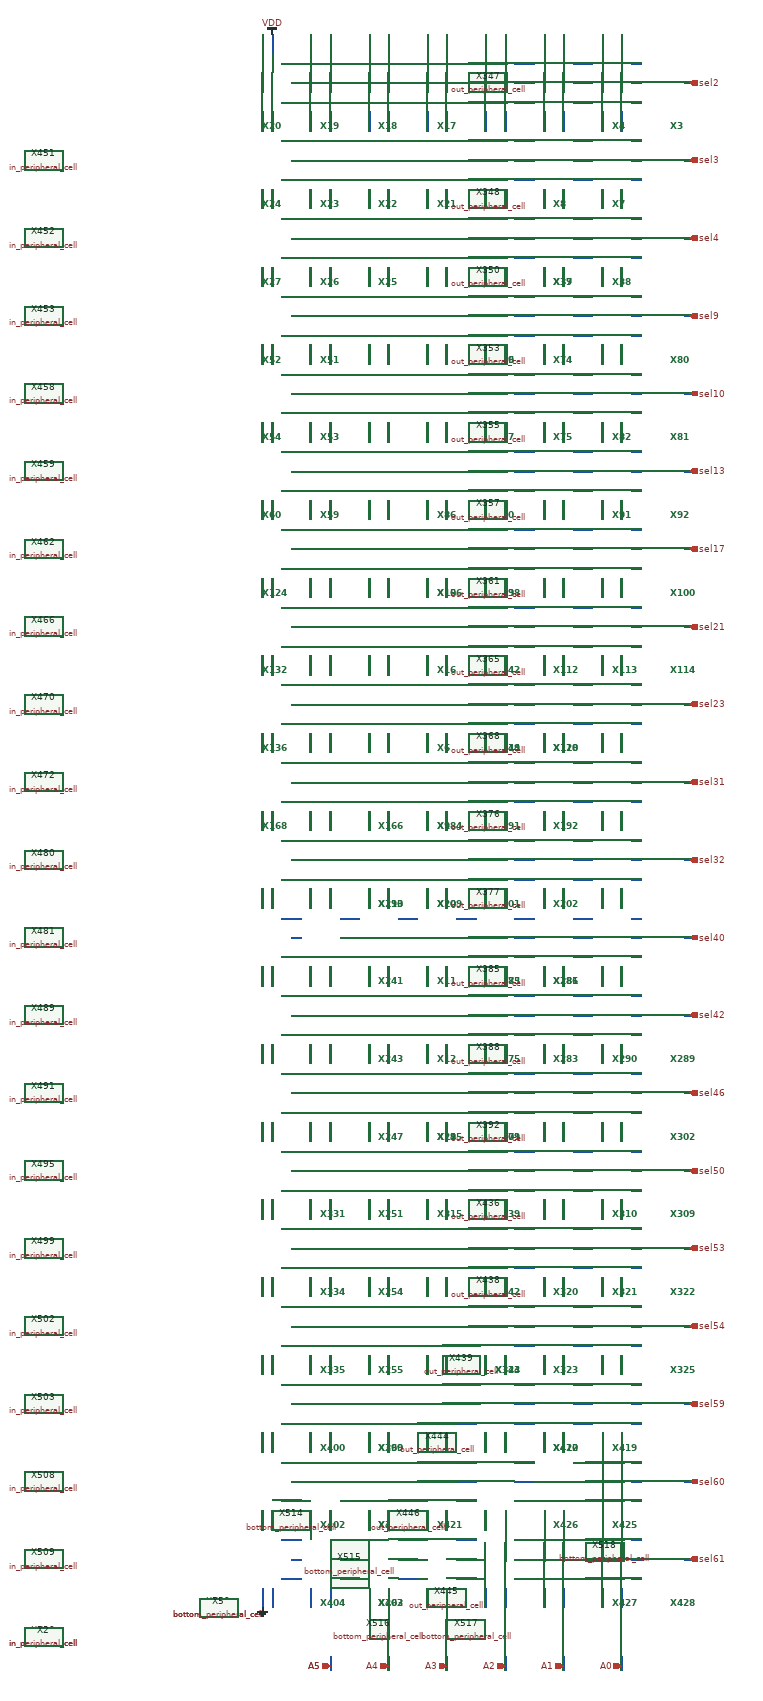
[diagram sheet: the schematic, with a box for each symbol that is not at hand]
v {xschem version=2.9.9 file_version=1.2 }
G {}
K {}
V {}
S {}
E {}
N 7700 7730 7700 7760 { lab=A5}
N 7820 7730 7820 7760 { lab=A4}
N 7940 7730 7940 7760 { lab=A3}
N 8060 7730 8060 7760 { lab=A2}
N 8180 7730 8180 7760 { lab=A1}
N 8300 7730 8300 7760 { lab=A0}
N 8430 7530 8450 7530 { lab=sel61}
N 8430 7370 8450 7370 { lab=sel60}
N 8430 7210 8450 7210 { lab=sel59}
N 8430 7050 8450 7050 { lab=sel54}
N 8430 6890 8450 6890 { lab=sel53}
N 8430 6730 8450 6730 { lab=sel50}
N 8430 6570 8450 6570 { lab=sel46}
N 8430 6410 8450 6410 { lab=sel42}
N 8430 6250 8450 6250 { lab=sel40}
N 8430 5930 8450 5930 { lab=sel31}
N 8430 5770 8450 5770 { lab=sel23}
N 8430 5450 8450 5450 { lab=sel17}
N 8430 5290 8450 5290 { lab=sel13}
N 8430 5130 8450 5130 { lab=sel10}
N 8430 4970 8450 4970 { lab=sel9}
N 8430 4810 8450 4810 { lab=sel4}
N 8430 4650 8450 4650 { lab=sel3}
N 8430 4490 8450 4490 { lab=sel2}
N 7560 4390 7560 4430 { lab=#net1}
N 7580 4390 7580 4430 { lab=VDD}
N 7660 4390 7660 4430 { lab=#net2}
N 7700 4390 7700 4430 { lab=#net3}
N 7780 4390 7780 4430 { lab=#net4}
N 7820 4390 7820 4430 { lab=#net5}
N 7900 4390 7900 4430 { lab=#net6}
N 7940 4390 7940 4430 { lab=#net7}
N 8020 4390 8020 4430 { lab=#net8}
N 8060 4390 8060 4430 { lab=#net9}
N 8140 4390 8140 4430 { lab=#net10}
N 8180 4390 8180 4430 { lab=#net11}
N 8260 4390 8260 4430 { lab=#net12}
N 8300 4390 8300 4430 { lab=#net13}
N 7600 4450 7640 4450 { lab=#net14}
N 7600 4530 7640 4530 { lab=#net15}
N 7720 4450 7760 4450 { lab=#net16}
N 7720 4490 7760 4490 { lab=#net17}
N 7720 4530 7760 4530 { lab=#net18}
N 7840 4450 7880 4450 { lab=#net19}
N 7840 4490 7880 4490 { lab=#net20}
N 7840 4530 7880 4530 { lab=#net21}
N 7960 4450 8000 4450 { lab=#net22}
N 7960 4490 8000 4490 { lab=#net23}
N 7960 4530 8000 4530 { lab=#net24}
N 8080 4450 8120 4450 { lab=#net25}
N 8080 4490 8120 4490 { lab=#net26}
N 8080 4530 8120 4530 { lab=#net27}
N 8200 4450 8240 4450 { lab=#net28}
N 8200 4490 8240 4490 { lab=#net29}
N 8200 4530 8240 4530 { lab=#net30}
N 8320 4490 8340 4490 { lab=#net31}
N 8320 4530 8340 4530 { lab=#net32}
N 7560 4550 7560 4590 { lab=#net33}
N 7580 4550 7580 4590 { lab=#net34}
N 7660 4550 7660 4590 { lab=#net35}
N 7700 4550 7700 4590 { lab=#net36}
N 7780 4550 7780 4590 { lab=#net37}
N 7820 4550 7820 4590 { lab=#net38}
N 7900 4550 7900 4590 { lab=#net39}
N 7940 4550 7940 4590 { lab=#net40}
N 8020 4550 8020 4590 { lab=#net41}
N 8060 4550 8060 4590 { lab=#net42}
N 8140 4550 8140 4590 { lab=#net43}
N 8180 4550 8180 4590 { lab=#net44}
N 8260 4550 8260 4590 { lab=#net45}
N 8300 4550 8300 4590 { lab=#net46}
N 7600 4610 7640 4610 { lab=#net47}
N 7600 4690 7640 4690 { lab=#net48}
N 7720 4610 7760 4610 { lab=#net49}
N 7720 4650 7760 4650 { lab=#net50}
N 7720 4690 7760 4690 { lab=#net51}
N 7840 4610 7880 4610 { lab=#net52}
N 7840 4650 7880 4650 { lab=#net53}
N 7840 4690 7880 4690 { lab=#net54}
N 7960 4610 8000 4610 { lab=#net55}
N 7960 4650 8000 4650 { lab=#net56}
N 7960 4690 8000 4690 { lab=#net57}
N 8080 4610 8120 4610 { lab=#net58}
N 8080 4650 8120 4650 { lab=#net59}
N 8080 4690 8120 4690 { lab=#net60}
N 8200 4610 8240 4610 { lab=#net61}
N 8200 4650 8240 4650 { lab=#net62}
N 8200 4690 8240 4690 { lab=#net63}
N 8320 4650 8340 4650 { lab=#net64}
N 8320 4690 8340 4690 { lab=#net65}
N 7560 4710 7560 4750 { lab=#net66}
N 7580 4710 7580 4750 { lab=#net67}
N 7660 4710 7660 4750 { lab=#net68}
N 7700 4710 7700 4750 { lab=#net69}
N 7780 4710 7780 4750 { lab=#net70}
N 7820 4710 7820 4750 { lab=#net71}
N 7900 4710 7900 4750 { lab=#net72}
N 7940 4710 7940 4750 { lab=#net73}
N 8020 4710 8020 4750 { lab=#net74}
N 8060 4710 8060 4750 { lab=#net75}
N 8140 4710 8140 4750 { lab=#net76}
N 8180 4710 8180 4750 { lab=#net77}
N 8260 4710 8260 4750 { lab=#net78}
N 8300 4710 8300 4750 { lab=#net79}
N 7600 4770 7640 4770 { lab=#net80}
N 7720 4770 7760 4770 { lab=#net81}
N 7720 4810 7760 4810 { lab=#net82}
N 7840 4770 7880 4770 { lab=#net83}
N 7840 4810 7880 4810 { lab=#net84}
N 7960 4770 8000 4770 { lab=#net85}
N 7960 4810 8000 4810 { lab=#net86}
N 8080 4770 8120 4770 { lab=#net87}
N 8080 4810 8120 4810 { lab=#net88}
N 8200 4770 8240 4770 { lab=#net89}
N 8200 4810 8240 4810 { lab=#net90}
N 8320 4810 8340 4810 { lab=#net91}
N 7560 4870 7560 4910 { lab=#net92}
N 7580 4870 7580 4910 { lab=#net93}
N 7660 4870 7660 4910 { lab=#net94}
N 7700 4870 7700 4910 { lab=#net95}
N 7780 4870 7780 4910 { lab=#net96}
N 7820 4870 7820 4910 { lab=#net97}
N 7900 4870 7900 4910 { lab=#net98}
N 7940 4870 7940 4910 { lab=#net99}
N 8020 4870 8020 4910 { lab=#net100}
N 8060 4870 8060 4910 { lab=#net101}
N 8140 4870 8140 4910 { lab=#net102}
N 8180 4870 8180 4910 { lab=#net103}
N 8260 4870 8260 4910 { lab=#net104}
N 8300 4870 8300 4910 { lab=#net105}
N 7600 4930 7640 4930 { lab=#net106}
N 7600 5010 7640 5010 { lab=#net107}
N 7720 4930 7760 4930 { lab=#net108}
N 7720 4970 7760 4970 { lab=#net109}
N 7720 5010 7760 5010 { lab=#net110}
N 7840 4930 7880 4930 { lab=#net111}
N 7840 4970 7880 4970 { lab=#net112}
N 7840 5010 7880 5010 { lab=#net113}
N 7960 4930 8000 4930 { lab=#net114}
N 7960 4970 8000 4970 { lab=#net115}
N 7960 5010 8000 5010 { lab=#net116}
N 8080 4930 8120 4930 { lab=#net117}
N 8080 4970 8120 4970 { lab=#net118}
N 8080 5010 8120 5010 { lab=#net119}
N 8200 4930 8240 4930 { lab=#net120}
N 8200 4970 8240 4970 { lab=#net121}
N 8200 5010 8240 5010 { lab=#net122}
N 8320 4970 8340 4970 { lab=#net123}
N 8320 5010 8340 5010 { lab=#net124}
N 7560 5030 7560 5070 { lab=#net125}
N 7580 5030 7580 5070 { lab=#net126}
N 7660 5030 7660 5070 { lab=#net127}
N 7700 5030 7700 5070 { lab=#net128}
N 7780 5030 7780 5070 { lab=#net129}
N 7820 5030 7820 5070 { lab=#net130}
N 7900 5030 7900 5070 { lab=#net131}
N 7940 5030 7940 5070 { lab=#net132}
N 8020 5030 8020 5070 { lab=#net133}
N 8060 5030 8060 5070 { lab=#net134}
N 8140 5030 8140 5070 { lab=#net135}
N 8180 5030 8180 5070 { lab=#net136}
N 8260 5030 8260 5070 { lab=#net137}
N 8300 5030 8300 5070 { lab=#net138}
N 7600 5090 7640 5090 { lab=#net139}
N 7720 5090 7760 5090 { lab=#net140}
N 7720 5130 7760 5130 { lab=#net141}
N 7840 5090 7880 5090 { lab=#net142}
N 7840 5130 7880 5130 { lab=#net143}
N 7960 5090 8000 5090 { lab=#net144}
N 7960 5130 8000 5130 { lab=#net145}
N 8080 5090 8120 5090 { lab=#net146}
N 8080 5130 8120 5130 { lab=#net147}
N 8200 5090 8240 5090 { lab=#net148}
N 8200 5130 8240 5130 { lab=#net149}
N 8320 5130 8340 5130 { lab=#net150}
N 7560 5190 7560 5230 { lab=#net151}
N 7580 5190 7580 5230 { lab=#net152}
N 7660 5190 7660 5230 { lab=#net153}
N 7700 5190 7700 5230 { lab=#net154}
N 7780 5190 7780 5230 { lab=#net155}
N 7820 5190 7820 5230 { lab=#net156}
N 7900 5190 7900 5230 { lab=#net157}
N 7940 5190 7940 5230 { lab=#net158}
N 8020 5190 8020 5230 { lab=#net159}
N 8060 5190 8060 5230 { lab=#net160}
N 8140 5190 8140 5230 { lab=#net161}
N 8180 5190 8180 5230 { lab=#net162}
N 8260 5190 8260 5230 { lab=#net163}
N 8300 5190 8300 5230 { lab=#net164}
N 7600 5250 7640 5250 { lab=#net165}
N 7720 5250 7760 5250 { lab=#net166}
N 7720 5290 7760 5290 { lab=#net167}
N 7840 5250 7880 5250 { lab=#net168}
N 7840 5290 7880 5290 { lab=#net169}
N 7960 5250 8000 5250 { lab=#net170}
N 7960 5290 8000 5290 { lab=#net171}
N 8080 5250 8120 5250 { lab=#net172}
N 8080 5290 8120 5290 { lab=#net173}
N 8200 5250 8240 5250 { lab=#net174}
N 8200 5290 8240 5290 { lab=#net175}
N 8320 5290 8340 5290 { lab=#net176}
N 7560 5350 7560 5390 { lab=#net177}
N 7580 5350 7580 5390 { lab=#net178}
N 7660 5350 7660 5390 { lab=#net179}
N 7700 5350 7700 5390 { lab=#net180}
N 7780 5350 7780 5390 { lab=#net181}
N 7820 5350 7820 5390 { lab=#net182}
N 7900 5350 7900 5390 { lab=#net183}
N 7940 5350 7940 5390 { lab=#net184}
N 8020 5350 8020 5390 { lab=#net185}
N 8060 5350 8060 5390 { lab=#net186}
N 8140 5350 8140 5390 { lab=#net187}
N 8180 5350 8180 5390 { lab=#net188}
N 8260 5350 8260 5390 { lab=#net189}
N 8300 5350 8300 5390 { lab=#net190}
N 7600 5410 7640 5410 { lab=#net191}
N 7720 5410 7760 5410 { lab=#net192}
N 7720 5450 7760 5450 { lab=#net193}
N 7840 5410 7880 5410 { lab=#net194}
N 7840 5450 7880 5450 { lab=#net195}
N 7960 5410 8000 5410 { lab=#net196}
N 7960 5450 8000 5450 { lab=#net197}
N 8080 5410 8120 5410 { lab=#net198}
N 8080 5450 8120 5450 { lab=#net199}
N 8200 5410 8240 5410 { lab=#net200}
N 8200 5450 8240 5450 { lab=#net201}
N 8320 5450 8340 5450 { lab=#net202}
N 7560 5510 7560 5550 { lab=#net203}
N 7580 5510 7580 5550 { lab=#net204}
N 7660 5510 7660 5550 { lab=#net205}
N 7700 5510 7700 5550 { lab=#net206}
N 7900 5510 7900 5550 { lab=#net209}
N 7940 5510 7940 5550 { lab=#net210}
N 8020 5510 8020 5550 { lab=#net211}
N 8060 5510 8060 5550 { lab=#net212}
N 8140 5510 8140 5550 { lab=#net213}
N 8180 5510 8180 5550 { lab=#net214}
N 8260 5510 8260 5550 { lab=#net215}
N 8300 5510 8300 5550 { lab=#net216}
N 7600 5570 7640 5570 { lab=#net217}
N 7720 5570 7760 5570 { lab=#net218}
N 7840 5570 7880 5570 { lab=#net219}
N 7960 5570 8000 5570 { lab=#net220}
N 8080 5570 8120 5570 { lab=#net221}
N 8200 5570 8240 5570 { lab=#net222}
N 7560 5670 7560 5710 { lab=#net223}
N 7580 5670 7580 5710 { lab=#net224}
N 7660 5670 7660 5710 { lab=#net225}
N 7700 5670 7700 5710 { lab=#net226}
N 7900 5670 7900 5710 { lab=#net229}
N 7940 5670 7940 5710 { lab=#net230}
N 8020 5670 8020 5710 { lab=#net231}
N 8060 5670 8060 5710 { lab=#net232}
N 8140 5670 8140 5710 { lab=#net233}
N 8180 5670 8180 5710 { lab=#net234}
N 8260 5670 8260 5710 { lab=#net235}
N 8300 5670 8300 5710 { lab=#net236}
N 7600 5730 7640 5730 { lab=#net237}
N 7720 5730 7760 5730 { lab=#net238}
N 7720 5770 7760 5770 { lab=#net239}
N 7840 5730 7880 5730 { lab=#net240}
N 7840 5770 7880 5770 { lab=#net241}
N 7960 5730 8000 5730 { lab=#net242}
N 7960 5770 8000 5770 { lab=#net243}
N 8080 5730 8120 5730 { lab=#net244}
N 8080 5770 8120 5770 { lab=#net245}
N 8200 5730 8240 5730 { lab=#net246}
N 8200 5770 8240 5770 { lab=#net247}
N 8320 5770 8340 5770 { lab=#net248}
N 7560 5830 7560 5870 { lab=#net249}
N 7580 5830 7580 5870 { lab=#net250}
N 7660 5830 7660 5870 { lab=#net251}
N 7700 5830 7700 5870 { lab=#net252}
N 7900 5830 7900 5870 { lab=#net255}
N 7940 5830 7940 5870 { lab=#net256}
N 8020 5830 8020 5870 { lab=#net257}
N 8060 5830 8060 5870 { lab=#net258}
N 8140 5830 8140 5870 { lab=#net259}
N 8180 5830 8180 5870 { lab=#net260}
N 8260 5830 8260 5870 { lab=#net261}
N 8300 5830 8300 5870 { lab=#net262}
N 7600 5890 7640 5890 { lab=#net263}
N 7600 5970 7640 5970 { lab=#net264}
N 7720 5890 7760 5890 { lab=#net265}
N 7720 5930 7760 5930 { lab=#net266}
N 7720 5970 7760 5970 { lab=#net267}
N 7840 5890 7880 5890 { lab=#net268}
N 7840 5930 7880 5930 { lab=#net269}
N 7840 5970 7880 5970 { lab=#net270}
N 7960 5890 8000 5890 { lab=#net271}
N 7960 5930 8000 5930 { lab=#net272}
N 7960 5970 8000 5970 { lab=#net273}
N 8080 5890 8120 5890 { lab=#net274}
N 8080 5930 8120 5930 { lab=#net275}
N 8080 5970 8120 5970 { lab=#net276}
N 8200 5890 8240 5890 { lab=#net277}
N 8200 5930 8240 5930 { lab=#net278}
N 8200 5970 8240 5970 { lab=#net279}
N 8320 5930 8340 5930 { lab=#net280}
N 8320 5970 8340 5970 { lab=#net281}
N 7560 5990 7560 6030 { lab=#net282}
N 7580 5990 7580 6030 { lab=#net283}
N 7660 5990 7660 6030 { lab=#net284}
N 7700 5990 7700 6030 { lab=#net285}
N 7900 5990 7900 6030 { lab=#net288}
N 7940 5990 7940 6030 { lab=#net289}
N 8020 5990 8020 6030 { lab=#net290}
N 8060 5990 8060 6030 { lab=#net291}
N 8140 5990 8140 6030 { lab=#net292}
N 8180 5990 8180 6030 { lab=#net293}
N 8260 5990 8260 6030 { lab=#net294}
N 8300 5990 8300 6030 { lab=#net295}
N 7600 6050 7640 6050 { lab=#net296}
N 7720 6050 7760 6050 { lab=#net297}
N 7840 6050 7880 6050 { lab=#net298}
N 7960 6050 8000 6050 { lab=#net299}
N 8080 6050 8120 6050 { lab=#net300}
N 8200 6050 8240 6050 { lab=#net301}
N 7560 6150 7560 6190 { lab=#net302}
N 7580 6150 7580 6190 { lab=#net303}
N 7660 6150 7660 6190 { lab=#net304}
N 7700 6150 7700 6190 { lab=#net305}
N 7900 6150 7900 6190 { lab=#net308}
N 7940 6150 7940 6190 { lab=#net309}
N 8020 6150 8020 6190 { lab=#net310}
N 8060 6150 8060 6190 { lab=#net311}
N 8140 6150 8140 6190 { lab=#net312}
N 8180 6150 8180 6190 { lab=#net313}
N 8260 6150 8260 6190 { lab=#net314}
N 8300 6150 8300 6190 { lab=#net315}
N 7600 6210 7640 6210 { lab=#net316}
N 7720 6210 7760 6210 { lab=#net317}
N 7840 6210 7880 6210 { lab=#net318}
N 7960 6210 8000 6210 { lab=#net319}
N 8080 6210 8120 6210 { lab=#net320}
N 8200 6210 8240 6210 { lab=#net321}
N 7600 6210 7640 6210 { lab=#net316}
N 7720 6210 7760 6210 { lab=#net317}
N 7720 6250 7760 6250 { lab=#net322}
N 7840 6210 7880 6210 { lab=#net318}
N 7840 6250 7880 6250 { lab=#net323}
N 7960 6210 8000 6210 { lab=#net319}
N 7960 6250 8000 6250 { lab=#net324}
N 8080 6210 8120 6210 { lab=#net320}
N 8080 6250 8120 6250 { lab=#net325}
N 8200 6210 8240 6210 { lab=#net321}
N 8200 6250 8240 6250 { lab=#net326}
N 8320 6250 8340 6250 { lab=#net327}
N 7560 6310 7560 6350 { lab=#net328}
N 7580 6310 7580 6350 { lab=#net329}
N 7660 6310 7660 6350 { lab=#net330}
N 7700 6310 7700 6350 { lab=#net331}
N 7900 6310 7900 6350 { lab=#net334}
N 7940 6310 7940 6350 { lab=#net335}
N 8020 6310 8020 6350 { lab=#net336}
N 8060 6310 8060 6350 { lab=#net337}
N 8140 6310 8140 6350 { lab=#net338}
N 8180 6310 8180 6350 { lab=#net339}
N 8260 6310 8260 6350 { lab=#net340}
N 8300 6310 8300 6350 { lab=#net341}
N 7600 6370 7640 6370 { lab=#net342}
N 7720 6370 7760 6370 { lab=#net343}
N 7720 6410 7760 6410 { lab=#net344}
N 7840 6370 7880 6370 { lab=#net345}
N 7840 6410 7880 6410 { lab=#net346}
N 7960 6370 8000 6370 { lab=#net347}
N 7960 6410 8000 6410 { lab=#net348}
N 8080 6370 8120 6370 { lab=#net349}
N 8080 6410 8120 6410 { lab=#net350}
N 8200 6370 8240 6370 { lab=#net351}
N 8200 6410 8240 6410 { lab=#net352}
N 8320 6410 8340 6410 { lab=#net353}
N 7560 6470 7560 6510 { lab=#net354}
N 7580 6470 7580 6510 { lab=#net355}
N 7660 6470 7660 6510 { lab=#net356}
N 7700 6470 7700 6510 { lab=#net357}
N 7900 6470 7900 6510 { lab=#net360}
N 7940 6470 7940 6510 { lab=#net361}
N 8020 6470 8020 6510 { lab=#net362}
N 8060 6470 8060 6510 { lab=#net363}
N 8140 6470 8140 6510 { lab=#net364}
N 8180 6470 8180 6510 { lab=#net365}
N 8260 6470 8260 6510 { lab=#net366}
N 8300 6470 8300 6510 { lab=#net367}
N 7600 6530 7640 6530 { lab=#net368}
N 7720 6530 7760 6530 { lab=#net369}
N 7720 6570 7760 6570 { lab=#net370}
N 7840 6530 7880 6530 { lab=#net371}
N 7840 6570 7880 6570 { lab=#net372}
N 7960 6530 8000 6530 { lab=#net373}
N 7960 6570 8000 6570 { lab=#net374}
N 8080 6530 8120 6530 { lab=#net375}
N 8080 6570 8120 6570 { lab=#net376}
N 8200 6530 8240 6530 { lab=#net377}
N 8200 6570 8240 6570 { lab=#net378}
N 8320 6570 8340 6570 { lab=#net379}
N 7560 6630 7560 6670 { lab=#net380}
N 7580 6630 7580 6670 { lab=#net381}
N 7660 6630 7660 6670 { lab=#net382}
N 7700 6630 7700 6670 { lab=#net383}
N 7780 6630 7780 6670 { lab=#net384}
N 7820 6630 7820 6670 { lab=#net385}
N 7900 6630 7900 6670 { lab=#net386}
N 7940 6630 7940 6670 { lab=#net387}
N 8020 6630 8020 6670 { lab=#net388}
N 8060 6630 8060 6670 { lab=#net389}
N 8140 6630 8140 6670 { lab=#net390}
N 8180 6630 8180 6670 { lab=#net391}
N 8260 6630 8260 6670 { lab=#net392}
N 8300 6630 8300 6670 { lab=#net393}
N 7600 6690 7640 6690 { lab=#net394}
N 7720 6690 7760 6690 { lab=#net395}
N 7720 6730 7760 6730 { lab=#net396}
N 7840 6690 7880 6690 { lab=#net397}
N 7840 6730 7880 6730 { lab=#net398}
N 7960 6690 8000 6690 { lab=#net399}
N 7960 6730 8000 6730 { lab=#net400}
N 8080 6690 8120 6690 { lab=#net401}
N 8080 6730 8120 6730 { lab=#net402}
N 8200 6690 8240 6690 { lab=#net403}
N 8200 6730 8240 6730 { lab=#net404}
N 8320 6730 8340 6730 { lab=#net405}
N 8320 6210 8340 6210 { lab=#net406}
N 7620 6250 7640 6250 { lab=#net407}
N 7560 6790 7560 6830 { lab=#net408}
N 7580 6790 7580 6830 { lab=#net409}
N 7660 6790 7660 6830 { lab=#net410}
N 7700 6790 7700 6830 { lab=#net411}
N 7780 6790 7780 6830 { lab=#net412}
N 7820 6790 7820 6830 { lab=#net413}
N 7900 6790 7900 6830 { lab=#net414}
N 7940 6790 7940 6830 { lab=#net415}
N 8020 6790 8020 6830 { lab=#net416}
N 8060 6790 8060 6830 { lab=#net417}
N 8140 6790 8140 6830 { lab=#net418}
N 8180 6790 8180 6830 { lab=#net419}
N 8260 6790 8260 6830 { lab=#net420}
N 8300 6790 8300 6830 { lab=#net421}
N 7600 6850 7640 6850 { lab=#net422}
N 7600 6930 7640 6930 { lab=#net423}
N 7720 6850 7760 6850 { lab=#net424}
N 7720 6890 7760 6890 { lab=#net425}
N 7720 6930 7760 6930 { lab=#net426}
N 7840 6850 7880 6850 { lab=#net427}
N 7840 6890 7880 6890 { lab=#net428}
N 7840 6930 7880 6930 { lab=#net429}
N 7960 6850 8000 6850 { lab=#net430}
N 7960 6890 8000 6890 { lab=#net431}
N 7960 6930 8000 6930 { lab=#net432}
N 8080 6850 8120 6850 { lab=#net433}
N 8080 6890 8120 6890 { lab=#net434}
N 8080 6930 8120 6930 { lab=#net435}
N 8200 6850 8240 6850 { lab=#net436}
N 8200 6890 8240 6890 { lab=#net437}
N 8200 6930 8240 6930 { lab=#net438}
N 8320 6890 8340 6890 { lab=#net439}
N 8320 6930 8340 6930 { lab=#net440}
N 7560 6950 7560 6990 { lab=#net441}
N 7580 6950 7580 6990 { lab=#net442}
N 7660 6950 7660 6990 { lab=#net443}
N 7700 6950 7700 6990 { lab=#net444}
N 7780 6950 7780 6990 { lab=#net445}
N 7820 6950 7820 6990 { lab=#net446}
N 7900 6950 7900 6990 { lab=#net447}
N 7940 6950 7940 6990 { lab=#net448}
N 8020 6950 8020 6990 { lab=#net449}
N 8060 6950 8060 6990 { lab=#net450}
N 8140 6950 8140 6990 { lab=#net451}
N 8180 6950 8180 6990 { lab=#net452}
N 8260 6950 8260 6990 { lab=#net453}
N 8300 6950 8300 6990 { lab=#net454}
N 7600 7010 7640 7010 { lab=#net455}
N 7600 7090 7640 7090 { lab=#net456}
N 7720 7010 7760 7010 { lab=#net457}
N 7720 7050 7760 7050 { lab=#net458}
N 7720 7090 7760 7090 { lab=#net459}
N 7840 7010 7880 7010 { lab=#net460}
N 7840 7050 7880 7050 { lab=#net461}
N 7840 7090 7880 7090 { lab=#net462}
N 7960 7010 8000 7010 { lab=#net463}
N 7960 7050 8000 7050 { lab=#net464}
N 7960 7090 8000 7090 { lab=#net465}
N 8080 7010 8120 7010 { lab=#net466}
N 8080 7050 8120 7050 { lab=#net467}
N 8080 7090 8120 7090 { lab=#net468}
N 8200 7010 8240 7010 { lab=#net469}
N 8200 7050 8240 7050 { lab=#net470}
N 8200 7090 8240 7090 { lab=#net471}
N 8320 7050 8340 7050 { lab=#net472}
N 8320 7090 8340 7090 { lab=#net473}
N 7560 7110 7560 7150 { lab=#net474}
N 7580 7110 7580 7150 { lab=#net475}
N 7660 7110 7660 7150 { lab=#net476}
N 7700 7110 7700 7150 { lab=#net477}
N 7780 7110 7780 7150 { lab=#net478}
N 7820 7110 7820 7150 { lab=#net479}
N 7900 7110 7900 7150 { lab=#net480}
N 7940 7110 7940 7150 { lab=#net481}
N 8020 7110 8020 7150 { lab=#net482}
N 8060 7110 8060 7150 { lab=#net483}
N 8140 7110 8140 7150 { lab=#net484}
N 8180 7110 8180 7150 { lab=#net485}
N 8260 7110 8260 7150 { lab=#net486}
N 8300 7110 8300 7150 { lab=#net487}
N 7600 7170 7640 7170 { lab=#net488}
N 7600 7250 7640 7250 { lab=#net489}
N 7720 7170 7760 7170 { lab=#net490}
N 7720 7210 7760 7210 { lab=#net491}
N 7720 7250 7760 7250 { lab=#net492}
N 7840 7170 7880 7170 { lab=#net493}
N 7840 7210 7880 7210 { lab=#net494}
N 7840 7250 7880 7250 { lab=#net495}
N 7960 7170 8000 7170 { lab=#net496}
N 7960 7210 8000 7210 { lab=#net497}
N 7960 7250 8000 7250 { lab=#net498}
N 8080 7170 8120 7170 { lab=#net499}
N 8080 7210 8120 7210 { lab=#net500}
N 8080 7250 8120 7250 { lab=#net501}
N 8200 7170 8240 7170 { lab=#net502}
N 8200 7210 8240 7210 { lab=#net503}
N 8200 7250 8240 7250 { lab=#net504}
N 8320 7210 8340 7210 { lab=#net505}
N 8320 7250 8340 7250 { lab=#net506}
N 7560 7270 7560 7310 { lab=#net507}
N 7580 7270 7580 7310 { lab=#net508}
N 7660 7270 7660 7310 { lab=#net509}
N 7700 7270 7700 7310 { lab=#net510}
N 7780 7270 7780 7310 { lab=#net511}
N 7820 7270 7820 7310 { lab=#net512}
N 7900 7270 7900 7310 { lab=#net513}
N 7940 7270 7940 7310 { lab=#net514}
N 8020 7270 8020 7310 { lab=#net515}
N 8060 7270 8060 7310 { lab=#net516}
N 8140 7270 8140 7310 { lab=#net517}
N 8180 7270 8180 7310 { lab=#net518}
N 8260 7270 8260 7310 { lab=#net519}
N 8300 7270 8300 7310 { lab=#net520}
N 7600 7330 7640 7330 { lab=#net521}
N 7600 7410 7640 7410 { lab=#net522}
N 7720 7330 7760 7330 { lab=#net523}
N 7720 7370 7760 7370 { lab=#net524}
N 7720 7410 7760 7410 { lab=#net525}
N 7840 7330 7880 7330 { lab=#net526}
N 7840 7370 7880 7370 { lab=#net527}
N 7840 7410 7880 7410 { lab=#net528}
N 7960 7330 8000 7330 { lab=#net529}
N 7960 7370 8000 7370 { lab=#net530}
N 7960 7410 8000 7410 { lab=#net531}
N 8080 7330 8120 7330 { lab=#net532}
N 8080 7370 8120 7370 { lab=#net533}
N 8080 7410 8120 7410 { lab=#net534}
N 8200 7330 8240 7330 { lab=#net535}
N 8200 7370 8240 7370 { lab=#net536}
N 8200 7410 8240 7410 { lab=#net537}
N 8320 7370 8340 7370 { lab=#net538}
N 8320 7410 8340 7410 { lab=#net539}
N 7560 7430 7560 7470 { lab=#net540}
N 7580 7430 7580 7470 { lab=#net541}
N 7660 7430 7660 7470 { lab=#net542}
N 7700 7430 7700 7470 { lab=#net543}
N 7780 7430 7780 7470 { lab=#net544}
N 7820 7430 7820 7470 { lab=#net545}
N 7900 7430 7900 7470 { lab=#net546}
N 7940 7430 7940 7470 { lab=#net547}
N 8020 7430 8020 7470 { lab=#net548}
N 8060 7430 8060 7470 { lab=#net549}
N 8140 7430 8140 7470 { lab=#net550}
N 8180 7430 8180 7470 { lab=#net551}
N 8260 7430 8260 7470 { lab=#net552}
N 8300 7430 8300 7470 { lab=#net553}
N 7600 7490 7640 7490 { lab=#net554}
N 7600 7570 7640 7570 { lab=#net555}
N 7720 7490 7760 7490 { lab=#net556}
N 7720 7530 7760 7530 { lab=#net557}
N 7720 7570 7760 7570 { lab=#net558}
N 7840 7490 7880 7490 { lab=#net559}
N 7840 7530 7880 7530 { lab=#net560}
N 7840 7570 7880 7570 { lab=#net561}
N 7960 7490 8000 7490 { lab=#net562}
N 7960 7530 8000 7530 { lab=#net563}
N 7960 7570 8000 7570 { lab=#net564}
N 8080 7490 8120 7490 { lab=#net565}
N 8080 7530 8120 7530 { lab=#net566}
N 8080 7570 8120 7570 { lab=#net567}
N 8200 7490 8240 7490 { lab=#net568}
N 8200 7530 8240 7530 { lab=#net569}
N 8200 7570 8240 7570 { lab=#net570}
N 8320 7530 8340 7530 { lab=#net571}
N 8320 7570 8340 7570 { lab=#net572}
N 7560 7590 7560 7630 { lab=GND}
N 7580 7590 7580 7630 { lab=#net573}
N 7660 7590 7660 7630 { lab=#net574}
N 7700 7590 7700 7630 { lab=#net575}
N 7780 7590 7780 7630 { lab=#net576}
N 7820 7590 7820 7630 { lab=#net577}
N 7900 7590 7900 7630 { lab=#net578}
N 7940 7590 7940 7630 { lab=#net579}
N 8020 7590 8020 7630 { lab=#net580}
N 8060 7590 8060 7630 { lab=#net581}
N 8140 7590 8140 7630 { lab=#net582}
N 8180 7590 8180 7630 { lab=#net583}
N 8260 7590 8260 7630 { lab=#net584}
N 8300 7590 8300 7630 { lab=#net585}
N 7620 4490 7640 4490 { lab=#net586}
N 8320 4450 8340 4450 { lab=#net587}
N 8320 4610 8340 4610 { lab=#net588}
N 7620 4650 7640 4650 { lab=#net589}
N 7620 4810 7640 4810 { lab=#net590}
N 8320 4770 8340 4770 { lab=#net591}
N 8320 4930 8340 4930 { lab=#net592}
N 7620 4970 7640 4970 { lab=#net593}
N 7620 5130 7640 5130 { lab=#net594}
N 8320 5090 8340 5090 { lab=#net595}
N 7620 5290 7640 5290 { lab=#net596}
N 8320 5250 8340 5250 { lab=#net597}
N 7620 5450 7640 5450 { lab=#net598}
N 8320 5410 8340 5410 { lab=#net599}
N 8320 5570 8340 5570 { lab=#net600}
N 7620 5770 7640 5770 { lab=#net601}
N 8320 5730 8340 5730 { lab=#net602}
N 7620 5930 7640 5930 { lab=#net603}
N 8320 5890 8340 5890 { lab=#net604}
N 8320 6050 8340 6050 { lab=#net605}
N 7620 6250 7640 6250 { lab=#net407}
N 8320 6210 8340 6210 { lab=#net406}
N 7620 6410 7640 6410 { lab=#net606}
N 8320 6370 8340 6370 { lab=#net607}
N 7620 6570 7640 6570 { lab=#net608}
N 8320 6530 8340 6530 { lab=#net609}
N 8320 6690 8340 6690 { lab=#net610}
N 7620 6730 7640 6730 { lab=#net611}
N 8320 6850 8340 6850 { lab=#net612}
N 7620 6890 7640 6890 { lab=#net613}
N 7620 7050 7640 7050 { lab=#net614}
N 8320 7010 8340 7010 { lab=#net615}
N 8320 7170 8340 7170 { lab=#net616}
N 7620 7210 7640 7210 { lab=#net617}
N 7620 7370 7640 7370 { lab=#net618}
N 8320 7330 8340 7330 { lab=#net619}
N 7620 7530 7640 7530 { lab=#net620}
N 8320 7490 8340 7490 { lab=#net621}
N 8320 6770 8340 6770 { lab=#net622}
N 8320 4850 8340 4850 { lab=#net623}
N 8320 5170 8340 5170 { lab=#net624}
N 8320 5330 8340 5330 { lab=#net625}
N 8320 5490 8340 5490 { lab=#net626}
N 8320 5610 8340 5610 { lab=#net627}
N 8320 5650 8340 5650 { lab=#net628}
N 8320 5810 8340 5810 { lab=#net629}
N 8320 6090 8340 6090 { lab=#net630}
N 8320 6130 8340 6130 { lab=#net631}
N 8320 6290 8340 6290 { lab=#net632}
N 8320 6450 8340 6450 { lab=#net633}
N 8320 6610 8340 6610 { lab=#net634}
N 8430 6090 8450 6090 { lab=sel32}
N 7600 4850 7640 4850 { lab=#net635}
N 7720 4850 7760 4850 { lab=#net636}
N 7840 4850 7880 4850 { lab=#net637}
N 7960 4850 8000 4850 { lab=#net638}
N 8080 4850 8120 4850 { lab=#net639}
N 8200 4850 8240 4850 { lab=#net640}
N 7600 5170 7640 5170 { lab=#net641}
N 7720 5170 7760 5170 { lab=#net642}
N 7840 5170 7880 5170 { lab=#net643}
N 7960 5170 8000 5170 { lab=#net644}
N 8080 5170 8120 5170 { lab=#net645}
N 8200 5170 8240 5170 { lab=#net646}
N 7600 5330 7640 5330 { lab=#net647}
N 7720 5330 7760 5330 { lab=#net648}
N 7840 5330 7880 5330 { lab=#net649}
N 7960 5330 8000 5330 { lab=#net650}
N 8080 5330 8120 5330 { lab=#net651}
N 8200 5330 8240 5330 { lab=#net652}
N 7600 5490 7640 5490 { lab=#net653}
N 7720 5490 7760 5490 { lab=#net654}
N 7840 5490 7880 5490 { lab=#net655}
N 7960 5490 8000 5490 { lab=#net656}
N 8080 5490 8120 5490 { lab=#net657}
N 8200 5490 8240 5490 { lab=#net658}
N 7600 5650 7640 5650 { lab=#net659}
N 7720 5650 7760 5650 { lab=#net660}
N 7840 5650 7880 5650 { lab=#net661}
N 7620 5610 7640 5610 { lab=#net662}
N 7720 5610 7760 5610 { lab=#net663}
N 7840 5610 7880 5610 { lab=#net664}
N 7960 5610 8000 5610 { lab=#net665}
N 7960 5650 8000 5650 { lab=#net666}
N 8080 5610 8120 5610 { lab=#net667}
N 8080 5650 8120 5650 { lab=#net668}
N 8200 5610 8240 5610 { lab=#net669}
N 8200 5650 8240 5650 { lab=#net670}
N 7600 5810 7640 5810 { lab=#net671}
N 7720 5810 7760 5810 { lab=#net672}
N 7840 5810 7880 5810 { lab=#net673}
N 7960 5810 8000 5810 { lab=#net674}
N 8080 5810 8120 5810 { lab=#net675}
N 8200 5810 8240 5810 { lab=#net676}
N 7620 6090 7640 6090 { lab=#net677}
N 7720 6090 7760 6090 { lab=#net678}
N 7840 6090 7880 6090 { lab=#net679}
N 7960 6090 8000 6090 { lab=#net680}
N 8080 6090 8120 6090 { lab=#net681}
N 8200 6090 8240 6090 { lab=#net682}
N 8200 6130 8240 6130 { lab=#net683}
N 8080 6130 8120 6130 { lab=#net684}
N 7960 6130 8000 6130 { lab=#net685}
N 7840 6130 7880 6130 { lab=#net686}
N 7720 6130 7760 6130 { lab=#net687}
N 7600 6130 7640 6130 { lab=#net688}
N 7600 6290 7640 6290 { lab=#net689}
N 7720 6290 7760 6290 { lab=#net690}
N 7840 6290 7880 6290 { lab=#net691}
N 7960 6290 8000 6290 { lab=#net692}
N 8080 6290 8120 6290 { lab=#net693}
N 8200 6290 8240 6290 { lab=#net694}
N 7600 6450 7640 6450 { lab=#net695}
N 7720 6450 7760 6450 { lab=#net696}
N 7840 6450 7880 6450 { lab=#net697}
N 7960 6450 8000 6450 { lab=#net698}
N 8080 6450 8120 6450 { lab=#net699}
N 8200 6450 8240 6450 { lab=#net700}
N 7600 6610 7640 6610 { lab=#net701}
N 7720 6610 7760 6610 { lab=#net702}
N 7840 6610 7880 6610 { lab=#net703}
N 7960 6610 8000 6610 { lab=#net704}
N 8080 6610 8120 6610 { lab=#net705}
N 8200 6610 8240 6610 { lab=#net706}
N 7600 6770 7640 6770 { lab=#net707}
N 7720 6770 7760 6770 { lab=#net708}
N 7840 6770 7880 6770 { lab=#net709}
N 7960 6770 8000 6770 { lab=#net710}
N 8080 6770 8120 6770 { lab=#net711}
N 8200 6770 8240 6770 { lab=#net712}
N 8430 5610 8450 5610 { lab=sel21}
N 7700 7730 7700 7760 { lab=A5}
N 7600 7490 7640 7490 { lab=#net554}
N 7600 7570 7640 7570 { lab=#net555}
N 7560 7590 7560 7630 { lab=GND}
N 7580 7590 7580 7630 { lab=#net573}
N 7660 7590 7660 7630 { lab=#net574}
N 7700 7590 7700 7630 { lab=#net575}
N 7620 7530 7640 7530 { lab=#net620}
N 7780 5830 7780 5870 { lab=#net410}
N 7820 5830 7820 5870 { lab=#net411}
N 7780 5990 7780 6030 { lab=#net443}
N 7820 5990 7820 6030 { lab=#net444}
N 7780 6150 7780 6190 { lab=#net476}
N 7820 6150 7820 6190 { lab=#net477}
N 7780 6310 7780 6350 { lab=#net509}
N 7820 6310 7820 6350 { lab=#net510}
N 7780 6470 7780 6510 { lab=#net542}
N 7820 6470 7820 6510 { lab=#net543}
N 7780 5510 7780 5550 { lab=#net410}
N 7820 5510 7820 5550 { lab=#net411}
N 7780 5670 7780 5710 {}
N 7820 5670 7820 5710 {}
C {decoder/decoder_cell_0.sym} 8400 4580 0 1 {name=X3}
C {decoder/decoder_cell_0.sym} 8280 4580 0 1 {name=X4}
C {decoder/decoder_cell_0.sym} 8280 4740 0 1 {name=X7}
C {decoder/decoder_cell_0.sym} 8160 4740 0 0 {name=X8}
C {decoder/decoder_cell_0.sym} 7920 4580 0 0 {name=X17}
C {decoder/decoder_cell_0.sym} 7800 4580 0 0 {name=X18}
C {decoder/decoder_cell_0.sym} 7680 4580 0 0 {name=X19}
C {decoder/decoder_cell_0.sym} 7560 4580 0 0 {name=X20}
C {decoder/decoder_cell_0.sym} 7920 4740 0 0 {name=X21}
C {decoder/decoder_cell_0.sym} 7800 4740 0 0 {name=X22}
C {decoder/decoder_cell_0.sym} 7680 4740 0 0 {name=X23}
C {decoder/decoder_cell_0.sym} 7560 4740 0 0 {name=X24}
C {decoder/decoder_cell_0.sym} 7800 4900 0 0 {name=X25}
C {decoder/decoder_cell_0.sym} 7680 4900 0 0 {name=X26}
C {decoder/decoder_cell_0.sym} 7560 4900 0 0 {name=X27}
C {decoder/decoder_cell_0.sym} 8160 4900 0 1 {name=X37}
C {decoder/decoder_cell_0.sym} 8280 4900 0 1 {name=X38}
C {decoder/decoder_cell_0.sym} 8160 4900 0 0 {name=X39}
C {decoder/decoder_cell_0.sym} 7680 5060 0 0 {name=X51}
C {decoder/decoder_cell_0.sym} 7560 5060 0 0 {name=X52}
C {decoder/decoder_cell_0.sym} 7680 5220 0 0 {name=X53}
C {decoder/decoder_cell_0.sym} 7560 5220 0 0 {name=X54}
C {decoder/decoder_cell_0.sym} 7680 5380 0 0 {name=X59}
C {decoder/decoder_cell_0.sym} 7560 5380 0 0 {name=X60}
C {decoder/decoder_cell_0.sym} 8040 5060 0 1 {name=X66}
C {decoder/decoder_cell_0.sym} 8040 5220 0 1 {name=X67}
C {decoder/decoder_cell_0.sym} 8040 5380 0 1 {name=X70}
C {decoder/decoder_cell_0.sym} 8160 5060 0 1 {name=X74}
C {decoder/decoder_cell_0.sym} 8160 5220 0 1 {name=X75}
C {decoder/decoder_cell_0.sym} 8040 5060 0 0 {name=X79}
C {decoder/decoder_cell_0.sym} 8400 5060 0 1 {name=X80}
C {decoder/decoder_cell_0.sym} 8400 5220 0 1 {name=X81}
C {decoder/decoder_cell_0.sym} 8280 5220 0 1 {name=X82}
C {decoder/decoder_cell_0.sym} 7920 5380 0 0 {name=X86}
C {decoder/decoder_cell_0.sym} 8280 5380 0 1 {name=X91}
C {decoder/decoder_cell_0.sym} 8400 5380 0 1 {name=X92}
C {decoder/decoder_cell_0.sym} 8040 5540 0 0 {name=X99}
C {decoder/decoder_cell_0.sym} 8400 5540 0 1 {name=X100}
C {decoder/decoder_cell_0.sym} 7920 5540 0 0 {name=X106}
C {decoder/decoder_cell_0.sym} 8160 5700 0 1 {name=X112}
C {decoder/decoder_cell_0.sym} 8280 5700 0 1 {name=X113}
C {decoder/decoder_cell_0.sym} 8400 5700 0 1 {name=X114}
C {decoder/decoder_cell_0.sym} 8160 5860 0 1 {name=X118}
C {decoder/decoder_cell_0.sym} 8040 5860 0 0 {name=X119}
C {decoder/decoder_cell_0.sym} 8160 5860 0 0 {name=X120}
C {decoder/decoder_cell_0.sym} 7560 5540 0 0 {name=X124}
C {decoder/decoder_cell_0.sym} 7560 5700 0 0 {name=X132}
C {decoder/decoder_cell_0.sym} 7560 5860 0 0 {name=X136}
C {decoder/decoder_cell_0.sym} 8040 5540 0 1 {name=X138}
C {decoder/decoder_cell_0.sym} 8040 5700 0 1 {name=X142}
C {decoder/decoder_cell_0.sym} 8040 5860 0 1 {name=X144}
C {decoder/decoder_cell_0.sym} 7800 6020 0 0 {name=X166}
C {decoder/decoder_cell_0.sym} 7560 6020 0 0 {name=X168}
C {decoder/decoder_cell_0.sym} 7920 6020 0 0 {name=X184}
C {decoder/decoder_cell_0.sym} 8040 6020 0 0 {name=X191}
C {decoder/decoder_cell_0.sym} 8160 6020 0 0 {name=X192}
C {decoder/decoder_cell_0.sym} 7800 6180 0 1 {name=X193}
C {decoder/decoder_cell_0.sym} 8040 6180 0 0 {name=X201}
C {decoder/decoder_cell_0.sym} 8160 6180 0 0 {name=X202}
C {decoder/decoder_cell_0.sym} 7920 6180 0 0 {name=X209}
C {decoder/decoder_cell_0.sym} 7800 6180 0 0 {name=X210}
C {decoder/decoder_cell_0.sym} 7800 6340 0 1 {name=X241}
C {decoder/decoder_cell_0.sym} 7800 6500 0 1 {name=X243}
C {decoder/decoder_cell_0.sym} 7800 6660 0 1 {name=X247}
C {decoder/decoder_cell_0.sym} 7800 6820 0 1 {name=X251}
C {decoder/decoder_cell_0.sym} 7800 6980 0 1 {name=X254}
C {decoder/decoder_cell_0.sym} 7800 7140 0 1 {name=X255}
C {decoder/decoder_cell_0.sym} 7800 7300 0 1 {name=X260}
C {decoder/decoder_cell_0.sym} 7800 7460 0 1 {name=X261}
C {decoder/decoder_cell_0.sym} 7800 7620 0 1 {name=X262}
C {decoder/decoder_cell_0.sym} 8040 6340 0 1 {name=X273}
C {decoder/decoder_cell_0.sym} 8040 6500 0 1 {name=X275}
C {decoder/decoder_cell_0.sym} 8040 6660 0 1 {name=X279}
C {decoder/decoder_cell_0.sym} 8160 6340 0 1 {name=X281}
C {decoder/decoder_cell_0.sym} 8160 6500 0 1 {name=X283}
C {decoder/decoder_cell_0.sym} 8040 6340 0 0 {name=X285}
C {decoder/decoder_cell_0.sym} 8160 6340 0 0 {name=X286}
C {decoder/decoder_cell_0.sym} 8400 6500 0 1 {name=X289}
C {decoder/decoder_cell_0.sym} 8280 6500 0 1 {name=X290}
C {decoder/decoder_cell_0.sym} 7920 6660 0 0 {name=X295}
C {decoder/decoder_cell_0.sym} 8040 6660 0 0 {name=X301}
C {decoder/decoder_cell_0.sym} 8400 6660 0 1 {name=X302}
C {decoder/decoder_cell_0.sym} 8400 6820 0 1 {name=X309}
C {decoder/decoder_cell_0.sym} 8280 6820 0 1 {name=X310}
C {decoder/decoder_cell_0.sym} 7920 6820 0 0 {name=X315}
C {decoder/decoder_cell_0.sym} 8160 6980 0 1 {name=X320}
C {decoder/decoder_cell_0.sym} 8280 6980 0 1 {name=X321}
C {decoder/decoder_cell_0.sym} 8400 6980 0 1 {name=X322}
C {decoder/decoder_cell_0.sym} 8160 7140 0 1 {name=X323}
C {decoder/decoder_cell_0.sym} 8040 7140 0 0 {name=X324}
C {decoder/decoder_cell_0.sym} 8400 7140 0 1 {name=X325}
C {decoder/decoder_cell_0.sym} 7680 6820 0 0 {name=X331}
C {decoder/decoder_cell_0.sym} 7680 6980 0 0 {name=X334}
C {decoder/decoder_cell_0.sym} 7680 7140 0 0 {name=X335}
C {decoder/decoder_cell_0.sym} 8040 6820 0 1 {name=X339}
C {decoder/decoder_cell_0.sym} 8040 6980 0 1 {name=X342}
C {decoder/decoder_cell_0.sym} 8040 7140 0 1 {name=X343}
C {decoder/decoder_cell_0.sym} 7800 7300 0 0 {name=X399}
C {decoder/decoder_cell_0.sym} 7680 7300 0 0 {name=X400}
C {decoder/decoder_cell_0.sym} 7800 7460 0 0 {name=X401}
C {decoder/decoder_cell_0.sym} 7680 7460 0 0 {name=X402}
C {decoder/decoder_cell_0.sym} 7800 7620 0 0 {name=X403}
C {decoder/decoder_cell_0.sym} 7680 7620 0 0 {name=X404}
C {decoder/decoder_cell_0.sym} 8160 7300 0 1 {name=X412}
C {decoder/decoder_cell_0.sym} 8280 7300 0 1 {name=X419}
C {decoder/decoder_cell_0.sym} 8160 7300 0 0 {name=X420}
C {decoder/decoder_cell_0.sym} 7920 7460 0 0 {name=X421}
C {decoder/decoder_cell_0.sym} 7920 7620 0 0 {name=X422}
C {decoder/decoder_cell_0.sym} 8280 7460 0 1 {name=X425}
C {decoder/decoder_cell_0.sym} 8160 7460 0 0 {name=X426}
C {decoder/decoder_cell_0.sym} 8280 7620 0 1 {name=X427}
C {decoder/decoder_cell_0.sym} 8400 7620 0 1 {name=X428}
C {decoder/out_peripheral_cell.sym} 7860 4590 0 0 {name=X347}
C {decoder/out_peripheral_cell.sym} 7860 4750 0 0 {name=X348}
C {decoder/out_peripheral_cell.sym} 7860 4910 0 0 {name=X350}
C {decoder/out_peripheral_cell.sym} 7860 5070 0 0 {name=X353}
C {decoder/out_peripheral_cell.sym} 7860 5230 0 0 {name=X355}
C {decoder/out_peripheral_cell.sym} 7860 5390 0 0 {name=X357}
C {decoder/out_peripheral_cell.sym} 7860 5550 0 0 {name=X361}
C {decoder/out_peripheral_cell.sym} 7860 5710 0 0 {name=X365}
C {decoder/out_peripheral_cell.sym} 7860 5870 0 0 {name=X368}
C {decoder/out_peripheral_cell.sym} 7860 6030 0 0 {name=X376}
C {decoder/out_peripheral_cell.sym} 7860 6190 0 0 {name=X377}
C {decoder/out_peripheral_cell.sym} 7860 6350 0 0 {name=X385}
C {decoder/out_peripheral_cell.sym} 7860 6510 0 0 {name=X388}
C {decoder/out_peripheral_cell.sym} 7860 6670 0 0 {name=X392}
C {decoder/out_peripheral_cell.sym} 7860 6830 0 0 {name=X436}
C {decoder/out_peripheral_cell.sym} 7860 6990 0 0 {name=X438}
C {decoder/out_peripheral_cell.sym} 7860 7150 0 0 {name=X439}
C {decoder/out_peripheral_cell.sym} 7860 7310 0 0 {name=X444}
C {decoder/out_peripheral_cell.sym} 7860 7630 0 0 {name=X445}
C {decoder/out_peripheral_cell.sym} 7860 7470 0 0 {name=X446}
C {decoder/in_peripheral_cell.sym} 7110 4650 0 0 {name=X451}
C {decoder/in_peripheral_cell.sym} 7110 4810 0 0 {name=X452}
C {decoder/in_peripheral_cell.sym} 7110 4970 0 0 {name=X453}
C {decoder/in_peripheral_cell.sym} 7110 5130 0 0 {name=X458}
C {decoder/in_peripheral_cell.sym} 7110 5290 0 0 {name=X459}
C {decoder/in_peripheral_cell.sym} 7110 5450 0 0 {name=X462}
C {decoder/in_peripheral_cell.sym} 7110 5610 0 0 {name=X466}
C {decoder/in_peripheral_cell.sym} 7110 5770 0 0 {name=X470}
C {decoder/in_peripheral_cell.sym} 7110 5930 0 0 {name=X472}
C {decoder/in_peripheral_cell.sym} 7110 6090 0 0 {name=X480}
C {decoder/in_peripheral_cell.sym} 7110 6250 0 0 {name=X481}
C {decoder/in_peripheral_cell.sym} 7110 6410 0 0 {name=X489}
C {decoder/in_peripheral_cell.sym} 7110 6570 0 0 {name=X491}
C {decoder/in_peripheral_cell.sym} 7110 6730 0 0 {name=X495}
C {decoder/in_peripheral_cell.sym} 7110 6890 0 0 {name=X499}
C {decoder/in_peripheral_cell.sym} 7110 7050 0 0 {name=X502}
C {decoder/in_peripheral_cell.sym} 7110 7210 0 0 {name=X503}
C {decoder/in_peripheral_cell.sym} 7110 7370 0 0 {name=X508}
C {decoder/in_peripheral_cell.sym} 7110 7530 0 0 {name=X509}
C {decoder/in_peripheral_cell.sym} 7110 7690 0 0 {name=X510}
C {decoder/bottom_peripheral_cell.sym} 7470 7630 0 0 {name=X513}
C {decoder/bottom_peripheral_cell.sym} 7590 7630 0 0 {name=X514}
C {decoder/bottom_peripheral_cell.sym} 7710 7630 0 0 {name=X515}
C {decoder/bottom_peripheral_cell.sym} 7830 7630 0 0 {name=X516}
C {decoder/bottom_peripheral_cell.sym} 7950 7630 0 0 {name=X517}
C {decoder/bottom_peripheral_cell.sym} 8070 7630 0 0 {name=X518}
C {devices/ipin.sym} 7700 7750 3 0 {name=p3 lab=A5}
C {devices/ipin.sym} 7820 7750 3 0 {name=p4 lab=A4}
C {devices/ipin.sym} 7940 7750 3 0 {name=p5 lab=A3}
C {devices/ipin.sym} 8060 7750 3 0 {name=p6 lab=A2}
C {devices/ipin.sym} 8180 7750 3 0 {name=p7 lab=A1}
C {devices/ipin.sym} 8300 7750 3 0 {name=p8 lab=A0}
C {devices/opin.sym} 8440 7530 0 0 {name=p11 lab=sel61}
C {devices/opin.sym} 8440 7370 0 0 {name=p12 lab=sel60}
C {devices/opin.sym} 8440 7210 0 0 {name=p13 lab=sel59}
C {devices/opin.sym} 8440 7050 0 0 {name=p18 lab=sel54}
C {devices/opin.sym} 8440 6890 0 0 {name=p19 lab=sel53}
C {devices/opin.sym} 8440 6730 0 0 {name=p22 lab=sel50}
C {devices/opin.sym} 8440 6570 0 0 {name=p26 lab=sel46}
C {devices/opin.sym} 8440 6410 0 0 {name=p30 lab=sel42}
C {devices/opin.sym} 8440 6250 0 0 {name=p32 lab=sel40}
C {devices/opin.sym} 8440 5930 0 0 {name=p41 lab=sel31}
C {devices/opin.sym} 8440 5770 0 0 {name=p49 lab=sel23}
C {devices/opin.sym} 8440 5610 0 0 {name=p51 lab=sel21}
C {devices/opin.sym} 8440 5450 0 0 {name=p55 lab=sel17}
C {devices/opin.sym} 8440 5290 0 0 {name=p59 lab=sel13}
C {devices/opin.sym} 8440 5130 0 0 {name=p62 lab=sel10}
C {devices/opin.sym} 8440 4970 0 0 {name=p63 lab=sel9}
C {devices/opin.sym} 8440 4810 0 0 {name=p68 lab=sel4}
C {devices/opin.sym} 8440 4650 0 0 {name=p69 lab=sel3}
C {devices/opin.sym} 8440 4490 0 0 {name=p70 lab=sel2}
C {devices/vdd.sym} 7580 4390 0 0 {name=l1 lab=VDD}
C {devices/gnd.sym} 7560 7630 0 0 {name=l2 lab=GND}
C {devices/opin.sym} 8440 6090 0 0 {name=p1 lab=sel32}
C {decoder/decoder_cell_0.sym} 7800 7620 0 1 {name=X1}
C {decoder/in_peripheral_cell.sym} 7110 7690 0 0 {name=X2}
C {decoder/bottom_peripheral_cell.sym} 7470 7630 0 0 {name=X5}
C {devices/ipin.sym} 7700 7750 3 0 {name=p2 lab=A5}
C {devices/gnd.sym} 7560 7630 0 0 {name=l3 lab=GND}
C {decoder/decoder_cell_0.sym} 7920 5860 0 1 {name=X6}
C {decoder/decoder_cell_0.sym} 7920 6020 0 1 {name=X9}
C {decoder/decoder_cell_0.sym} 7920 6180 0 1 {name=X10}
C {decoder/decoder_cell_0.sym} 7920 6340 0 1 {name=X11}
C {decoder/decoder_cell_0.sym} 7920 6500 0 1 {name=X12}
C {decoder/decoder_cell_0.sym} 7920 6660 0 1 {name=X13}
C {decoder/decoder_cell_0.sym} 7920 6660 0 1 {name=X14}
C {decoder/decoder_cell_0.sym} 7920 5540 0 1 {name=X15}
C {decoder/decoder_cell_0.sym} 7920 5700 0 1 {name=X16}
